VERSION 5.7 ;
BUSBITCHARS "[]" ;
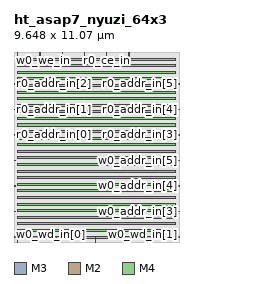
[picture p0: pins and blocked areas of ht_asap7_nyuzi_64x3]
MACRO ht_asap7_nyuzi_64x3
  FOREIGN ht_asap7_nyuzi_64x3 0 0 ;
  SYMMETRY X Y R90 ;
  SIZE 9.648 BY 11.070 ;
  CLASS BLOCK ;
  PIN w0_wd_in[0]
    DIRECTION INPUT ;
    USE SIGNAL ;
    SHAPE ABUTMENT ;
    PORT
      LAYER M3 ;
      RECT 0.000 0.276 0.072 0.300 ;
    END
  END w0_wd_in[0]
  PIN w0_wd_in[1]
    DIRECTION INPUT ;
    USE SIGNAL ;
    SHAPE ABUTMENT ;
    PORT
      LAYER M3 ;
      RECT 9.576 0.276 9.648 0.300 ;
    END
  END w0_wd_in[1]
  PIN w0_wd_in[2]
    DIRECTION INPUT ;
    USE SIGNAL ;
    SHAPE ABUTMENT ;
    PORT
      LAYER M2 ;
      RECT 0.207 0.000 0.225 0.270 ;
    END
  END w0_wd_in[2]
  PIN r0_rd_out[0]
    DIRECTION OUTPUT ;
    USE SIGNAL ;
    SHAPE ABUTMENT ;
    PORT
      LAYER M2 ;
      RECT 2.475 0.000 2.493 0.270 ;
    END
  END r0_rd_out[0]
  PIN r0_rd_out[1]
    DIRECTION OUTPUT ;
    USE SIGNAL ;
    SHAPE ABUTMENT ;
    PORT
      LAYER M2 ;
      RECT 4.743 0.000 4.761 0.270 ;
    END
  END r0_rd_out[1]
  PIN r0_rd_out[2]
    DIRECTION OUTPUT ;
    USE SIGNAL ;
    SHAPE ABUTMENT ;
    PORT
      LAYER M2 ;
      RECT 0.207 10.800 0.225 11.070 ;
    END
  END r0_rd_out[2]
  PIN w0_addr_in[0]
    DIRECTION INPUT ;
    USE SIGNAL ;
    SHAPE ABUTMENT ;
    PORT
      LAYER M3 ;
      RECT 0.000 1.764 0.072 1.788 ;
    END
  END w0_addr_in[0]
  PIN w0_addr_in[1]
    DIRECTION INPUT ;
    USE SIGNAL ;
    SHAPE ABUTMENT ;
    PORT
      LAYER M3 ;
      RECT 0.000 3.252 0.072 3.276 ;
    END
  END w0_addr_in[1]
  PIN w0_addr_in[2]
    DIRECTION INPUT ;
    USE SIGNAL ;
    SHAPE ABUTMENT ;
    PORT
      LAYER M3 ;
      RECT 0.000 4.740 0.072 4.764 ;
    END
  END w0_addr_in[2]
  PIN w0_addr_in[3]
    DIRECTION INPUT ;
    USE SIGNAL ;
    SHAPE ABUTMENT ;
    PORT
      LAYER M3 ;
      RECT 9.576 1.764 9.648 1.788 ;
    END
  END w0_addr_in[3]
  PIN w0_addr_in[4]
    DIRECTION INPUT ;
    USE SIGNAL ;
    SHAPE ABUTMENT ;
    PORT
      LAYER M3 ;
      RECT 9.576 3.252 9.648 3.276 ;
    END
  END w0_addr_in[4]
  PIN w0_addr_in[5]
    DIRECTION INPUT ;
    USE SIGNAL ;
    SHAPE ABUTMENT ;
    PORT
      LAYER M3 ;
      RECT 9.576 4.740 9.648 4.764 ;
    END
  END w0_addr_in[5]
  PIN r0_addr_in[0]
    DIRECTION INPUT ;
    USE SIGNAL ;
    SHAPE ABUTMENT ;
    PORT
      LAYER M3 ;
      RECT 0.000 6.228 0.072 6.252 ;
    END
  END r0_addr_in[0]
  PIN r0_addr_in[1]
    DIRECTION INPUT ;
    USE SIGNAL ;
    SHAPE ABUTMENT ;
    PORT
      LAYER M3 ;
      RECT 0.000 7.716 0.072 7.740 ;
    END
  END r0_addr_in[1]
  PIN r0_addr_in[2]
    DIRECTION INPUT ;
    USE SIGNAL ;
    SHAPE ABUTMENT ;
    PORT
      LAYER M3 ;
      RECT 0.000 9.204 0.072 9.228 ;
    END
  END r0_addr_in[2]
  PIN r0_addr_in[3]
    DIRECTION INPUT ;
    USE SIGNAL ;
    SHAPE ABUTMENT ;
    PORT
      LAYER M3 ;
      RECT 9.576 6.228 9.648 6.252 ;
    END
  END r0_addr_in[3]
  PIN r0_addr_in[4]
    DIRECTION INPUT ;
    USE SIGNAL ;
    SHAPE ABUTMENT ;
    PORT
      LAYER M3 ;
      RECT 9.576 7.716 9.648 7.740 ;
    END
  END r0_addr_in[4]
  PIN r0_addr_in[5]
    DIRECTION INPUT ;
    USE SIGNAL ;
    SHAPE ABUTMENT ;
    PORT
      LAYER M3 ;
      RECT 9.576 9.204 9.648 9.228 ;
    END
  END r0_addr_in[5]
  PIN w0_we_in
    DIRECTION INPUT ;
    USE SIGNAL ;
    SHAPE ABUTMENT ;
    PORT
      LAYER M2 ;
      RECT 1.503 10.800 1.521 11.070 ;
    END
  END w0_we_in
  PIN w0_ce_in
    DIRECTION INPUT ;
    USE SIGNAL ;
    SHAPE ABUTMENT ;
    PORT
      LAYER M2 ;
      RECT 2.799 10.800 2.817 11.070 ;
    END
  END w0_ce_in
  PIN w0_clk
    DIRECTION INPUT ;
    USE SIGNAL ;
    SHAPE ABUTMENT ;
    PORT
      LAYER M2 ;
      RECT 4.095 10.800 4.113 11.070 ;
    END
  END w0_clk
  PIN r0_ce_in
    DIRECTION INPUT ;
    USE SIGNAL ;
    SHAPE ABUTMENT ;
    PORT
      LAYER M2 ;
      RECT 5.391 10.800 5.409 11.070 ;
    END
  END r0_ce_in
  PIN r0_clk
    DIRECTION INPUT ;
    USE SIGNAL ;
    SHAPE ABUTMENT ;
    PORT
      LAYER M2 ;
      RECT 6.687 10.800 6.705 11.070 ;
    END
  END r0_clk
  PIN VSS
    DIRECTION INOUT ;
    USE GROUND ;
    PORT
      LAYER M4 ;
      RECT 0.216 0.228 9.432 0.348 ;
      RECT 0.216 0.996 9.432 1.116 ;
      RECT 0.216 1.764 9.432 1.884 ;
      RECT 0.216 2.532 9.432 2.652 ;
      RECT 0.216 3.300 9.432 3.420 ;
      RECT 0.216 4.068 9.432 4.188 ;
      RECT 0.216 4.836 9.432 4.956 ;
      RECT 0.216 5.604 9.432 5.724 ;
      RECT 0.216 6.372 9.432 6.492 ;
      RECT 0.216 7.140 9.432 7.260 ;
      RECT 0.216 7.908 9.432 8.028 ;
      RECT 0.216 8.676 9.432 8.796 ;
      RECT 0.216 9.444 9.432 9.564 ;
      RECT 0.216 10.212 9.432 10.332 ;
    END
  END VSS
  PIN VDD
    DIRECTION INOUT ;
    USE POWER ;
    PORT
      LAYER M4 ;
      RECT 0.216 0.612 9.432 0.732 ;
      RECT 0.216 1.380 9.432 1.500 ;
      RECT 0.216 2.148 9.432 2.268 ;
      RECT 0.216 2.916 9.432 3.036 ;
      RECT 0.216 3.684 9.432 3.804 ;
      RECT 0.216 4.452 9.432 4.572 ;
      RECT 0.216 5.220 9.432 5.340 ;
      RECT 0.216 5.988 9.432 6.108 ;
      RECT 0.216 6.756 9.432 6.876 ;
      RECT 0.216 7.524 9.432 7.644 ;
      RECT 0.216 8.292 9.432 8.412 ;
      RECT 0.216 9.060 9.432 9.180 ;
      RECT 0.216 9.828 9.432 9.948 ;
      RECT 0.216 10.596 9.432 10.716 ;
    END
  END VDD
  OBS
    LAYER M1 ;
    RECT 0 0 9.648 11.070 ;
    LAYER M2 ;
    RECT 0 0 9.648 11.070 ;
    LAYER M3 ;
    RECT 0 0 9.648 11.070 ;
    LAYER M4 ;
    RECT 0 0 9.648 11.070 ;
  END
END ht_asap7_nyuzi_64x3

END LIBRARY
